VERSION 5.7 ;
BUSBITCHARS "[]" ;
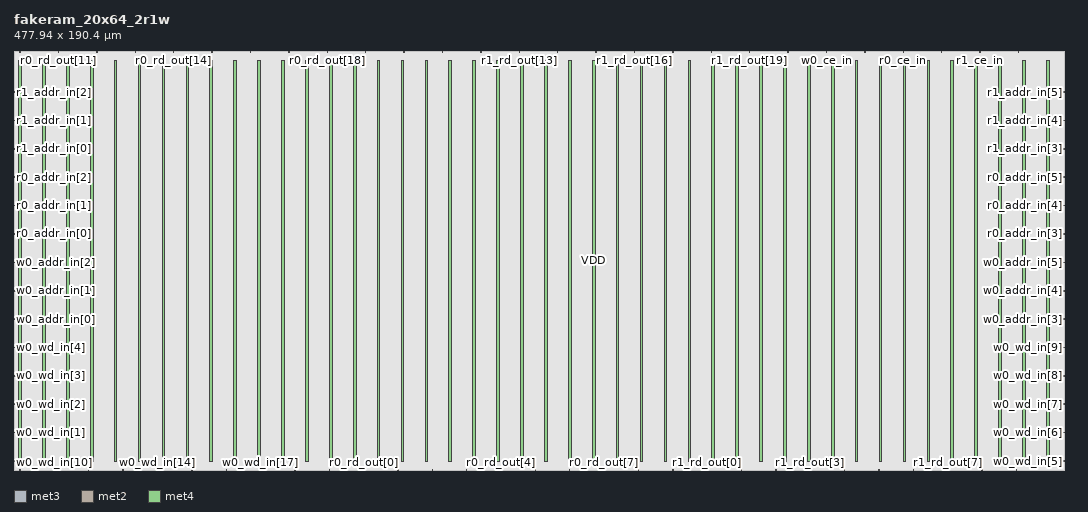
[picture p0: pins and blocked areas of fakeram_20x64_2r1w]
MACRO fakeram_20x64_2r1w
  FOREIGN fakeram_20x64_2r1w 0 0 ;
  SYMMETRY X Y R90 ;
  SIZE 477.940 BY 190.400 ;
  CLASS BLOCK ;
  PIN w0_wd_in[0]
    DIRECTION INPUT ;
    USE SIGNAL ;
    SHAPE ABUTMENT ;
    PORT
      LAYER met3 ;
      RECT 0.000 3.930 0.900 4.230 ;
    END
  END w0_wd_in[0]
  PIN w0_wd_in[1]
    DIRECTION INPUT ;
    USE SIGNAL ;
    SHAPE ABUTMENT ;
    PORT
      LAYER met3 ;
      RECT 0.000 16.850 0.900 17.150 ;
    END
  END w0_wd_in[1]
  PIN w0_wd_in[2]
    DIRECTION INPUT ;
    USE SIGNAL ;
    SHAPE ABUTMENT ;
    PORT
      LAYER met3 ;
      RECT 0.000 29.770 0.900 30.070 ;
    END
  END w0_wd_in[2]
  PIN w0_wd_in[3]
    DIRECTION INPUT ;
    USE SIGNAL ;
    SHAPE ABUTMENT ;
    PORT
      LAYER met3 ;
      RECT 0.000 42.690 0.900 42.990 ;
    END
  END w0_wd_in[3]
  PIN w0_wd_in[4]
    DIRECTION INPUT ;
    USE SIGNAL ;
    SHAPE ABUTMENT ;
    PORT
      LAYER met3 ;
      RECT 0.000 55.610 0.900 55.910 ;
    END
  END w0_wd_in[4]
  PIN w0_wd_in[5]
    DIRECTION INPUT ;
    USE SIGNAL ;
    SHAPE ABUTMENT ;
    PORT
      LAYER met3 ;
      RECT 477.040 3.930 477.940 4.230 ;
    END
  END w0_wd_in[5]
  PIN w0_wd_in[6]
    DIRECTION INPUT ;
    USE SIGNAL ;
    SHAPE ABUTMENT ;
    PORT
      LAYER met3 ;
      RECT 477.040 16.850 477.940 17.150 ;
    END
  END w0_wd_in[6]
  PIN w0_wd_in[7]
    DIRECTION INPUT ;
    USE SIGNAL ;
    SHAPE ABUTMENT ;
    PORT
      LAYER met3 ;
      RECT 477.040 29.770 477.940 30.070 ;
    END
  END w0_wd_in[7]
  PIN w0_wd_in[8]
    DIRECTION INPUT ;
    USE SIGNAL ;
    SHAPE ABUTMENT ;
    PORT
      LAYER met3 ;
      RECT 477.040 42.690 477.940 42.990 ;
    END
  END w0_wd_in[8]
  PIN w0_wd_in[9]
    DIRECTION INPUT ;
    USE SIGNAL ;
    SHAPE ABUTMENT ;
    PORT
      LAYER met3 ;
      RECT 477.040 55.610 477.940 55.910 ;
    END
  END w0_wd_in[9]
  PIN w0_wd_in[10]
    DIRECTION OUTPUT ;
    USE SIGNAL ;
    SHAPE ABUTMENT ;
    PORT
      LAYER met2 ;
      RECT 2.690 0.000 2.830 0.420 ;
    END
  END w0_wd_in[10]
  PIN w0_wd_in[11]
    DIRECTION OUTPUT ;
    USE SIGNAL ;
    SHAPE ABUTMENT ;
    PORT
      LAYER met2 ;
      RECT 18.330 0.000 18.470 0.420 ;
    END
  END w0_wd_in[11]
  PIN w0_wd_in[12]
    DIRECTION OUTPUT ;
    USE SIGNAL ;
    SHAPE ABUTMENT ;
    PORT
      LAYER met2 ;
      RECT 33.970 0.000 34.110 0.420 ;
    END
  END w0_wd_in[12]
  PIN w0_wd_in[13]
    DIRECTION OUTPUT ;
    USE SIGNAL ;
    SHAPE ABUTMENT ;
    PORT
      LAYER met2 ;
      RECT 49.610 0.000 49.750 0.420 ;
    END
  END w0_wd_in[13]
  PIN w0_wd_in[14]
    DIRECTION OUTPUT ;
    USE SIGNAL ;
    SHAPE ABUTMENT ;
    PORT
      LAYER met2 ;
      RECT 65.250 0.000 65.390 0.420 ;
    END
  END w0_wd_in[14]
  PIN w0_wd_in[15]
    DIRECTION OUTPUT ;
    USE SIGNAL ;
    SHAPE ABUTMENT ;
    PORT
      LAYER met2 ;
      RECT 80.890 0.000 81.030 0.420 ;
    END
  END w0_wd_in[15]
  PIN w0_wd_in[16]
    DIRECTION OUTPUT ;
    USE SIGNAL ;
    SHAPE ABUTMENT ;
    PORT
      LAYER met2 ;
      RECT 96.530 0.000 96.670 0.420 ;
    END
  END w0_wd_in[16]
  PIN w0_wd_in[17]
    DIRECTION OUTPUT ;
    USE SIGNAL ;
    SHAPE ABUTMENT ;
    PORT
      LAYER met2 ;
      RECT 112.170 0.000 112.310 0.420 ;
    END
  END w0_wd_in[17]
  PIN w0_wd_in[18]
    DIRECTION OUTPUT ;
    USE SIGNAL ;
    SHAPE ABUTMENT ;
    PORT
      LAYER met2 ;
      RECT 127.810 0.000 127.950 0.420 ;
    END
  END w0_wd_in[18]
  PIN w0_wd_in[19]
    DIRECTION OUTPUT ;
    USE SIGNAL ;
    SHAPE ABUTMENT ;
    PORT
      LAYER met2 ;
      RECT 143.450 0.000 143.590 0.420 ;
    END
  END w0_wd_in[19]
  PIN r0_rd_out[0]
    DIRECTION OUTPUT ;
    USE SIGNAL ;
    SHAPE ABUTMENT ;
    PORT
      LAYER met2 ;
      RECT 159.090 0.000 159.230 0.420 ;
    END
  END r0_rd_out[0]
  PIN r0_rd_out[1]
    DIRECTION OUTPUT ;
    USE SIGNAL ;
    SHAPE ABUTMENT ;
    PORT
      LAYER met2 ;
      RECT 174.730 0.000 174.870 0.420 ;
    END
  END r0_rd_out[1]
  PIN r0_rd_out[2]
    DIRECTION OUTPUT ;
    USE SIGNAL ;
    SHAPE ABUTMENT ;
    PORT
      LAYER met2 ;
      RECT 190.370 0.000 190.510 0.420 ;
    END
  END r0_rd_out[2]
  PIN r0_rd_out[3]
    DIRECTION OUTPUT ;
    USE SIGNAL ;
    SHAPE ABUTMENT ;
    PORT
      LAYER met2 ;
      RECT 206.010 0.000 206.150 0.420 ;
    END
  END r0_rd_out[3]
  PIN r0_rd_out[4]
    DIRECTION OUTPUT ;
    USE SIGNAL ;
    SHAPE ABUTMENT ;
    PORT
      LAYER met2 ;
      RECT 221.650 0.000 221.790 0.420 ;
    END
  END r0_rd_out[4]
  PIN r0_rd_out[5]
    DIRECTION OUTPUT ;
    USE SIGNAL ;
    SHAPE ABUTMENT ;
    PORT
      LAYER met2 ;
      RECT 237.290 0.000 237.430 0.420 ;
    END
  END r0_rd_out[5]
  PIN r0_rd_out[6]
    DIRECTION OUTPUT ;
    USE SIGNAL ;
    SHAPE ABUTMENT ;
    PORT
      LAYER met2 ;
      RECT 252.930 0.000 253.070 0.420 ;
    END
  END r0_rd_out[6]
  PIN r0_rd_out[7]
    DIRECTION OUTPUT ;
    USE SIGNAL ;
    SHAPE ABUTMENT ;
    PORT
      LAYER met2 ;
      RECT 268.570 0.000 268.710 0.420 ;
    END
  END r0_rd_out[7]
  PIN r0_rd_out[8]
    DIRECTION OUTPUT ;
    USE SIGNAL ;
    SHAPE ABUTMENT ;
    PORT
      LAYER met2 ;
      RECT 284.210 0.000 284.350 0.420 ;
    END
  END r0_rd_out[8]
  PIN r0_rd_out[9]
    DIRECTION OUTPUT ;
    USE SIGNAL ;
    SHAPE ABUTMENT ;
    PORT
      LAYER met2 ;
      RECT 299.850 0.000 299.990 0.420 ;
    END
  END r0_rd_out[9]
  PIN r0_rd_out[10]
    DIRECTION OUTPUT ;
    USE SIGNAL ;
    SHAPE ABUTMENT ;
    PORT
      LAYER met2 ;
      RECT 2.690 189.980 2.830 190.400 ;
    END
  END r0_rd_out[10]
  PIN r0_rd_out[11]
    DIRECTION OUTPUT ;
    USE SIGNAL ;
    SHAPE ABUTMENT ;
    PORT
      LAYER met2 ;
      RECT 20.170 189.980 20.310 190.400 ;
    END
  END r0_rd_out[11]
  PIN r0_rd_out[12]
    DIRECTION OUTPUT ;
    USE SIGNAL ;
    SHAPE ABUTMENT ;
    PORT
      LAYER met2 ;
      RECT 37.650 189.980 37.790 190.400 ;
    END
  END r0_rd_out[12]
  PIN r0_rd_out[13]
    DIRECTION OUTPUT ;
    USE SIGNAL ;
    SHAPE ABUTMENT ;
    PORT
      LAYER met2 ;
      RECT 55.130 189.980 55.270 190.400 ;
    END
  END r0_rd_out[13]
  PIN r0_rd_out[14]
    DIRECTION OUTPUT ;
    USE SIGNAL ;
    SHAPE ABUTMENT ;
    PORT
      LAYER met2 ;
      RECT 72.610 189.980 72.750 190.400 ;
    END
  END r0_rd_out[14]
  PIN r0_rd_out[15]
    DIRECTION OUTPUT ;
    USE SIGNAL ;
    SHAPE ABUTMENT ;
    PORT
      LAYER met2 ;
      RECT 90.090 189.980 90.230 190.400 ;
    END
  END r0_rd_out[15]
  PIN r0_rd_out[16]
    DIRECTION OUTPUT ;
    USE SIGNAL ;
    SHAPE ABUTMENT ;
    PORT
      LAYER met2 ;
      RECT 107.570 189.980 107.710 190.400 ;
    END
  END r0_rd_out[16]
  PIN r0_rd_out[17]
    DIRECTION OUTPUT ;
    USE SIGNAL ;
    SHAPE ABUTMENT ;
    PORT
      LAYER met2 ;
      RECT 125.050 189.980 125.190 190.400 ;
    END
  END r0_rd_out[17]
  PIN r0_rd_out[18]
    DIRECTION OUTPUT ;
    USE SIGNAL ;
    SHAPE ABUTMENT ;
    PORT
      LAYER met2 ;
      RECT 142.530 189.980 142.670 190.400 ;
    END
  END r0_rd_out[18]
  PIN r0_rd_out[19]
    DIRECTION OUTPUT ;
    USE SIGNAL ;
    SHAPE ABUTMENT ;
    PORT
      LAYER met2 ;
      RECT 160.010 189.980 160.150 190.400 ;
    END
  END r0_rd_out[19]
  PIN r1_rd_out[0]
    DIRECTION OUTPUT ;
    USE SIGNAL ;
    SHAPE ABUTMENT ;
    PORT
      LAYER met2 ;
      RECT 315.490 0.000 315.630 0.420 ;
    END
  END r1_rd_out[0]
  PIN r1_rd_out[1]
    DIRECTION OUTPUT ;
    USE SIGNAL ;
    SHAPE ABUTMENT ;
    PORT
      LAYER met2 ;
      RECT 331.130 0.000 331.270 0.420 ;
    END
  END r1_rd_out[1]
  PIN r1_rd_out[2]
    DIRECTION OUTPUT ;
    USE SIGNAL ;
    SHAPE ABUTMENT ;
    PORT
      LAYER met2 ;
      RECT 346.770 0.000 346.910 0.420 ;
    END
  END r1_rd_out[2]
  PIN r1_rd_out[3]
    DIRECTION OUTPUT ;
    USE SIGNAL ;
    SHAPE ABUTMENT ;
    PORT
      LAYER met2 ;
      RECT 362.410 0.000 362.550 0.420 ;
    END
  END r1_rd_out[3]
  PIN r1_rd_out[4]
    DIRECTION OUTPUT ;
    USE SIGNAL ;
    SHAPE ABUTMENT ;
    PORT
      LAYER met2 ;
      RECT 378.050 0.000 378.190 0.420 ;
    END
  END r1_rd_out[4]
  PIN r1_rd_out[5]
    DIRECTION OUTPUT ;
    USE SIGNAL ;
    SHAPE ABUTMENT ;
    PORT
      LAYER met2 ;
      RECT 393.690 0.000 393.830 0.420 ;
    END
  END r1_rd_out[5]
  PIN r1_rd_out[6]
    DIRECTION OUTPUT ;
    USE SIGNAL ;
    SHAPE ABUTMENT ;
    PORT
      LAYER met2 ;
      RECT 409.330 0.000 409.470 0.420 ;
    END
  END r1_rd_out[6]
  PIN r1_rd_out[7]
    DIRECTION OUTPUT ;
    USE SIGNAL ;
    SHAPE ABUTMENT ;
    PORT
      LAYER met2 ;
      RECT 424.970 0.000 425.110 0.420 ;
    END
  END r1_rd_out[7]
  PIN r1_rd_out[8]
    DIRECTION OUTPUT ;
    USE SIGNAL ;
    SHAPE ABUTMENT ;
    PORT
      LAYER met2 ;
      RECT 440.610 0.000 440.750 0.420 ;
    END
  END r1_rd_out[8]
  PIN r1_rd_out[9]
    DIRECTION OUTPUT ;
    USE SIGNAL ;
    SHAPE ABUTMENT ;
    PORT
      LAYER met2 ;
      RECT 456.250 0.000 456.390 0.420 ;
    END
  END r1_rd_out[9]
  PIN r1_rd_out[10]
    DIRECTION OUTPUT ;
    USE SIGNAL ;
    SHAPE ABUTMENT ;
    PORT
      LAYER met2 ;
      RECT 177.490 189.980 177.630 190.400 ;
    END
  END r1_rd_out[10]
  PIN r1_rd_out[11]
    DIRECTION OUTPUT ;
    USE SIGNAL ;
    SHAPE ABUTMENT ;
    PORT
      LAYER met2 ;
      RECT 194.970 189.980 195.110 190.400 ;
    END
  END r1_rd_out[11]
  PIN r1_rd_out[12]
    DIRECTION OUTPUT ;
    USE SIGNAL ;
    SHAPE ABUTMENT ;
    PORT
      LAYER met2 ;
      RECT 212.450 189.980 212.590 190.400 ;
    END
  END r1_rd_out[12]
  PIN r1_rd_out[13]
    DIRECTION OUTPUT ;
    USE SIGNAL ;
    SHAPE ABUTMENT ;
    PORT
      LAYER met2 ;
      RECT 229.930 189.980 230.070 190.400 ;
    END
  END r1_rd_out[13]
  PIN r1_rd_out[14]
    DIRECTION OUTPUT ;
    USE SIGNAL ;
    SHAPE ABUTMENT ;
    PORT
      LAYER met2 ;
      RECT 247.410 189.980 247.550 190.400 ;
    END
  END r1_rd_out[14]
  PIN r1_rd_out[15]
    DIRECTION OUTPUT ;
    USE SIGNAL ;
    SHAPE ABUTMENT ;
    PORT
      LAYER met2 ;
      RECT 264.890 189.980 265.030 190.400 ;
    END
  END r1_rd_out[15]
  PIN r1_rd_out[16]
    DIRECTION OUTPUT ;
    USE SIGNAL ;
    SHAPE ABUTMENT ;
    PORT
      LAYER met2 ;
      RECT 282.370 189.980 282.510 190.400 ;
    END
  END r1_rd_out[16]
  PIN r1_rd_out[17]
    DIRECTION OUTPUT ;
    USE SIGNAL ;
    SHAPE ABUTMENT ;
    PORT
      LAYER met2 ;
      RECT 299.850 189.980 299.990 190.400 ;
    END
  END r1_rd_out[17]
  PIN r1_rd_out[18]
    DIRECTION OUTPUT ;
    USE SIGNAL ;
    SHAPE ABUTMENT ;
    PORT
      LAYER met2 ;
      RECT 317.330 189.980 317.470 190.400 ;
    END
  END r1_rd_out[18]
  PIN r1_rd_out[19]
    DIRECTION OUTPUT ;
    USE SIGNAL ;
    SHAPE ABUTMENT ;
    PORT
      LAYER met2 ;
      RECT 334.810 189.980 334.950 190.400 ;
    END
  END r1_rd_out[19]
  PIN w0_addr_in[0]
    DIRECTION INPUT ;
    USE SIGNAL ;
    SHAPE ABUTMENT ;
    PORT
      LAYER met3 ;
      RECT 0.000 68.530 0.900 68.830 ;
    END
  END w0_addr_in[0]
  PIN w0_addr_in[1]
    DIRECTION INPUT ;
    USE SIGNAL ;
    SHAPE ABUTMENT ;
    PORT
      LAYER met3 ;
      RECT 0.000 81.450 0.900 81.750 ;
    END
  END w0_addr_in[1]
  PIN w0_addr_in[2]
    DIRECTION INPUT ;
    USE SIGNAL ;
    SHAPE ABUTMENT ;
    PORT
      LAYER met3 ;
      RECT 0.000 94.370 0.900 94.670 ;
    END
  END w0_addr_in[2]
  PIN w0_addr_in[3]
    DIRECTION INPUT ;
    USE SIGNAL ;
    SHAPE ABUTMENT ;
    PORT
      LAYER met3 ;
      RECT 477.040 68.530 477.940 68.830 ;
    END
  END w0_addr_in[3]
  PIN w0_addr_in[4]
    DIRECTION INPUT ;
    USE SIGNAL ;
    SHAPE ABUTMENT ;
    PORT
      LAYER met3 ;
      RECT 477.040 81.450 477.940 81.750 ;
    END
  END w0_addr_in[4]
  PIN w0_addr_in[5]
    DIRECTION INPUT ;
    USE SIGNAL ;
    SHAPE ABUTMENT ;
    PORT
      LAYER met3 ;
      RECT 477.040 94.370 477.940 94.670 ;
    END
  END w0_addr_in[5]
  PIN r0_addr_in[0]
    DIRECTION INPUT ;
    USE SIGNAL ;
    SHAPE ABUTMENT ;
    PORT
      LAYER met3 ;
      RECT 0.000 107.290 0.900 107.590 ;
    END
  END r0_addr_in[0]
  PIN r0_addr_in[1]
    DIRECTION INPUT ;
    USE SIGNAL ;
    SHAPE ABUTMENT ;
    PORT
      LAYER met3 ;
      RECT 0.000 120.210 0.900 120.510 ;
    END
  END r0_addr_in[1]
  PIN r0_addr_in[2]
    DIRECTION INPUT ;
    USE SIGNAL ;
    SHAPE ABUTMENT ;
    PORT
      LAYER met3 ;
      RECT 0.000 133.130 0.900 133.430 ;
    END
  END r0_addr_in[2]
  PIN r0_addr_in[3]
    DIRECTION INPUT ;
    USE SIGNAL ;
    SHAPE ABUTMENT ;
    PORT
      LAYER met3 ;
      RECT 477.040 107.290 477.940 107.590 ;
    END
  END r0_addr_in[3]
  PIN r0_addr_in[4]
    DIRECTION INPUT ;
    USE SIGNAL ;
    SHAPE ABUTMENT ;
    PORT
      LAYER met3 ;
      RECT 477.040 120.210 477.940 120.510 ;
    END
  END r0_addr_in[4]
  PIN r0_addr_in[5]
    DIRECTION INPUT ;
    USE SIGNAL ;
    SHAPE ABUTMENT ;
    PORT
      LAYER met3 ;
      RECT 477.040 133.130 477.940 133.430 ;
    END
  END r0_addr_in[5]
  PIN r1_addr_in[0]
    DIRECTION INPUT ;
    USE SIGNAL ;
    SHAPE ABUTMENT ;
    PORT
      LAYER met3 ;
      RECT 0.000 146.050 0.900 146.350 ;
    END
  END r1_addr_in[0]
  PIN r1_addr_in[1]
    DIRECTION INPUT ;
    USE SIGNAL ;
    SHAPE ABUTMENT ;
    PORT
      LAYER met3 ;
      RECT 0.000 158.970 0.900 159.270 ;
    END
  END r1_addr_in[1]
  PIN r1_addr_in[2]
    DIRECTION INPUT ;
    USE SIGNAL ;
    SHAPE ABUTMENT ;
    PORT
      LAYER met3 ;
      RECT 0.000 171.890 0.900 172.190 ;
    END
  END r1_addr_in[2]
  PIN r1_addr_in[3]
    DIRECTION INPUT ;
    USE SIGNAL ;
    SHAPE ABUTMENT ;
    PORT
      LAYER met3 ;
      RECT 477.040 146.050 477.940 146.350 ;
    END
  END r1_addr_in[3]
  PIN r1_addr_in[4]
    DIRECTION INPUT ;
    USE SIGNAL ;
    SHAPE ABUTMENT ;
    PORT
      LAYER met3 ;
      RECT 477.040 158.970 477.940 159.270 ;
    END
  END r1_addr_in[4]
  PIN r1_addr_in[5]
    DIRECTION INPUT ;
    USE SIGNAL ;
    SHAPE ABUTMENT ;
    PORT
      LAYER met3 ;
      RECT 477.040 171.890 477.940 172.190 ;
    END
  END r1_addr_in[5]
  PIN w0_we_in
    DIRECTION INPUT ;
    USE SIGNAL ;
    SHAPE ABUTMENT ;
    PORT
      LAYER met2 ;
      RECT 352.290 189.980 352.430 190.400 ;
    END
  END w0_we_in
  PIN w0_ce_in
    DIRECTION INPUT ;
    USE SIGNAL ;
    SHAPE ABUTMENT ;
    PORT
      LAYER met2 ;
      RECT 369.770 189.980 369.910 190.400 ;
    END
  END w0_ce_in
  PIN w0_clk
    DIRECTION INPUT ;
    USE SIGNAL ;
    SHAPE ABUTMENT ;
    PORT
      LAYER met2 ;
      RECT 387.250 189.980 387.390 190.400 ;
    END
  END w0_clk
  PIN r0_ce_in
    DIRECTION INPUT ;
    USE SIGNAL ;
    SHAPE ABUTMENT ;
    PORT
      LAYER met2 ;
      RECT 404.730 189.980 404.870 190.400 ;
    END
  END r0_ce_in
  PIN r0_clk
    DIRECTION INPUT ;
    USE SIGNAL ;
    SHAPE ABUTMENT ;
    PORT
      LAYER met2 ;
      RECT 422.210 189.980 422.350 190.400 ;
    END
  END r0_clk
  PIN r1_ce_in
    DIRECTION INPUT ;
    USE SIGNAL ;
    SHAPE ABUTMENT ;
    PORT
      LAYER met2 ;
      RECT 439.690 189.980 439.830 190.400 ;
    END
  END r1_ce_in
  PIN r1_clk
    DIRECTION INPUT ;
    USE SIGNAL ;
    SHAPE ABUTMENT ;
    PORT
      LAYER met2 ;
      RECT 457.170 189.980 457.310 190.400 ;
    END
  END r1_clk
  PIN VSS
    DIRECTION INOUT ;
    USE GROUND ;
    PORT
      LAYER met4 ;
      RECT 2.160 4.080 3.360 186.320 ;
      RECT 13.040 4.080 14.240 186.320 ;
      RECT 23.920 4.080 25.120 186.320 ;
      RECT 34.800 4.080 36.000 186.320 ;
      RECT 45.680 4.080 46.880 186.320 ;
      RECT 56.560 4.080 57.760 186.320 ;
      RECT 67.440 4.080 68.640 186.320 ;
      RECT 78.320 4.080 79.520 186.320 ;
      RECT 89.200 4.080 90.400 186.320 ;
      RECT 100.080 4.080 101.280 186.320 ;
      RECT 110.960 4.080 112.160 186.320 ;
      RECT 121.840 4.080 123.040 186.320 ;
      RECT 132.720 4.080 133.920 186.320 ;
      RECT 143.600 4.080 144.800 186.320 ;
      RECT 154.480 4.080 155.680 186.320 ;
      RECT 165.360 4.080 166.560 186.320 ;
      RECT 176.240 4.080 177.440 186.320 ;
      RECT 187.120 4.080 188.320 186.320 ;
      RECT 198.000 4.080 199.200 186.320 ;
      RECT 208.880 4.080 210.080 186.320 ;
      RECT 219.760 4.080 220.960 186.320 ;
      RECT 230.640 4.080 231.840 186.320 ;
      RECT 241.520 4.080 242.720 186.320 ;
      RECT 252.400 4.080 253.600 186.320 ;
      RECT 263.280 4.080 264.480 186.320 ;
      RECT 274.160 4.080 275.360 186.320 ;
      RECT 285.040 4.080 286.240 186.320 ;
      RECT 295.920 4.080 297.120 186.320 ;
      RECT 306.800 4.080 308.000 186.320 ;
      RECT 317.680 4.080 318.880 186.320 ;
      RECT 328.560 4.080 329.760 186.320 ;
      RECT 339.440 4.080 340.640 186.320 ;
      RECT 350.320 4.080 351.520 186.320 ;
      RECT 361.200 4.080 362.400 186.320 ;
      RECT 372.080 4.080 373.280 186.320 ;
      RECT 382.960 4.080 384.160 186.320 ;
      RECT 393.840 4.080 395.040 186.320 ;
      RECT 404.720 4.080 405.920 186.320 ;
      RECT 415.600 4.080 416.800 186.320 ;
      RECT 426.480 4.080 427.680 186.320 ;
      RECT 437.360 4.080 438.560 186.320 ;
      RECT 448.240 4.080 449.440 186.320 ;
      RECT 459.120 4.080 460.320 186.320 ;
      RECT 470.000 4.080 471.200 186.320 ;
    END
  END VSS
  PIN VDD
    DIRECTION INOUT ;
    USE POWER ;
    PORT
      LAYER met4 ;
      RECT 2.160 4.080 3.360 186.320 ;
      RECT 13.040 4.080 14.240 186.320 ;
      RECT 23.920 4.080 25.120 186.320 ;
      RECT 34.800 4.080 36.000 186.320 ;
      RECT 45.680 4.080 46.880 186.320 ;
      RECT 56.560 4.080 57.760 186.320 ;
      RECT 67.440 4.080 68.640 186.320 ;
      RECT 78.320 4.080 79.520 186.320 ;
      RECT 89.200 4.080 90.400 186.320 ;
      RECT 100.080 4.080 101.280 186.320 ;
      RECT 110.960 4.080 112.160 186.320 ;
      RECT 121.840 4.080 123.040 186.320 ;
      RECT 132.720 4.080 133.920 186.320 ;
      RECT 143.600 4.080 144.800 186.320 ;
      RECT 154.480 4.080 155.680 186.320 ;
      RECT 165.360 4.080 166.560 186.320 ;
      RECT 176.240 4.080 177.440 186.320 ;
      RECT 187.120 4.080 188.320 186.320 ;
      RECT 198.000 4.080 199.200 186.320 ;
      RECT 208.880 4.080 210.080 186.320 ;
      RECT 219.760 4.080 220.960 186.320 ;
      RECT 230.640 4.080 231.840 186.320 ;
      RECT 241.520 4.080 242.720 186.320 ;
      RECT 252.400 4.080 253.600 186.320 ;
      RECT 263.280 4.080 264.480 186.320 ;
      RECT 274.160 4.080 275.360 186.320 ;
      RECT 285.040 4.080 286.240 186.320 ;
      RECT 295.920 4.080 297.120 186.320 ;
      RECT 306.800 4.080 308.000 186.320 ;
      RECT 317.680 4.080 318.880 186.320 ;
      RECT 328.560 4.080 329.760 186.320 ;
      RECT 339.440 4.080 340.640 186.320 ;
      RECT 350.320 4.080 351.520 186.320 ;
      RECT 361.200 4.080 362.400 186.320 ;
      RECT 372.080 4.080 373.280 186.320 ;
      RECT 382.960 4.080 384.160 186.320 ;
      RECT 393.840 4.080 395.040 186.320 ;
      RECT 404.720 4.080 405.920 186.320 ;
      RECT 415.600 4.080 416.800 186.320 ;
      RECT 426.480 4.080 427.680 186.320 ;
      RECT 437.360 4.080 438.560 186.320 ;
      RECT 448.240 4.080 449.440 186.320 ;
      RECT 459.120 4.080 460.320 186.320 ;
      RECT 470.000 4.080 471.200 186.320 ;
    END
  END VDD
  OBS
    LAYER met1 ;
    RECT 0 0 477.940 190.400 ;
    LAYER met2 ;
    RECT 0 0 477.940 190.400 ;
    LAYER met3 ;
    RECT 0 0 477.940 190.400 ;
    LAYER met4 ;
    RECT 0 0 477.940 190.400 ;
  END
END fakeram_20x64_2r1w

END LIBRARY
